One B-rep face of a CAD part: STEP entity #308.
In plain terms, the planar face has unit normal (1, 0, 0).
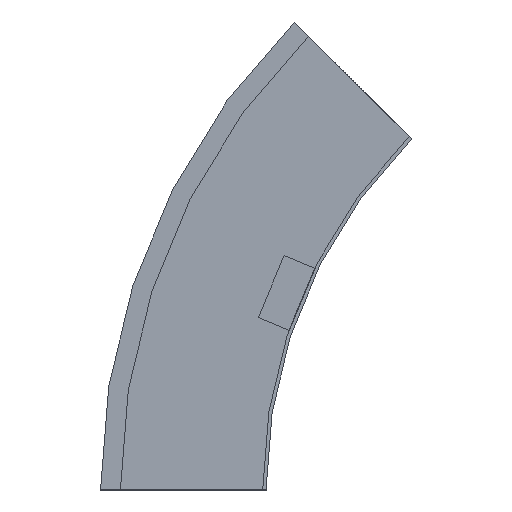
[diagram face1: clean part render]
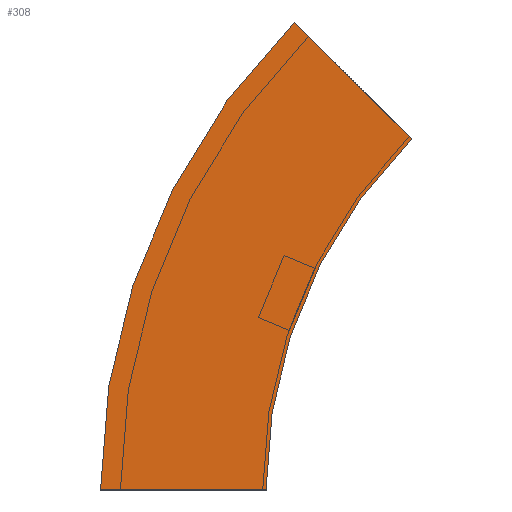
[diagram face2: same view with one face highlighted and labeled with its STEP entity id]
Its self-contained STEP definition (entity closure, numbers rounded to 3 decimals):
#50 = CARTESIAN_POINT ( 'NONE',  ( 0., -17.157, 282.843 ) ) ;
#55 = CIRCLE ( 'NONE', #179, 300. ) ;
#83 = CARTESIAN_POINT ( 'NONE',  ( 0., -300., 0. ) ) ;
#111 = EDGE_CURVE ( 'NONE', #306, #490, #560, .T. ) ;
#138 = DIRECTION ( 'NONE',  ( 0., 0.707, 0.707 ) ) ;
#150 = FACE_OUTER_BOUND ( 'NONE', #440, .T. ) ;
#179 = AXIS2_PLACEMENT_3D ( 'NONE', #83, #513, #252 ) ;
#220 = DIRECTION ( 'NONE',  ( 1., 0., 0. ) ) ;
#235 = CIRCLE ( 'NONE', #315, 400. ) ;
#252 = DIRECTION ( 'NONE',  ( 0., 1., 0. ) ) ;
#268 = EDGE_CURVE ( 'NONE', #329, #494, #563, .T. ) ;
#275 = DIRECTION ( 'NONE',  ( 1., 0., 0. ) ) ;
#286 = ORIENTED_EDGE ( 'NONE', *, *, #407, .T. ) ;
#306 = VERTEX_POINT ( 'NONE', #413 ) ;
#308 = ADVANCED_FACE ( 'NONE', ( #150 ), #336, .T. ) ;
#315 = AXIS2_PLACEMENT_3D ( 'NONE', #354, #220, #526 ) ;
#319 = CARTESIAN_POINT ( 'NONE',  ( 0., -87.868, 212.132 ) ) ;
#329 = VERTEX_POINT ( 'NONE', #406 ) ;
#332 = CARTESIAN_POINT ( 'NONE',  ( 0., 0., 0. ) ) ;
#336 = PLANE ( 'NONE',  #553 ) ;
#346 = CARTESIAN_POINT ( 'NONE',  ( 0., 100., 0. ) ) ;
#349 = CARTESIAN_POINT ( 'NONE',  ( 0., 0., 0. ) ) ;
#354 = CARTESIAN_POINT ( 'NONE',  ( 0., -300., 0. ) ) ;
#406 = CARTESIAN_POINT ( 'NONE',  ( 0., -87.868, 212.132 ) ) ;
#407 = EDGE_CURVE ( 'NONE', #490, #494, #235, .T. ) ;
#413 = CARTESIAN_POINT ( 'NONE',  ( 0., 0., 0. ) ) ;
#438 = VECTOR ( 'NONE', #516, 1000. ) ;
#439 = ORIENTED_EDGE ( 'NONE', *, *, #268, .F. ) ;
#440 = EDGE_LOOP ( 'NONE', ( #286, #439, #445, #550 ) ) ;
#443 = VECTOR ( 'NONE', #138, 1000. ) ;
#445 = ORIENTED_EDGE ( 'NONE', *, *, #500, .F. ) ;
#490 = VERTEX_POINT ( 'NONE', #346 ) ;
#494 = VERTEX_POINT ( 'NONE', #50 ) ;
#500 = EDGE_CURVE ( 'NONE', #306, #329, #55, .T. ) ;
#513 = DIRECTION ( 'NONE',  ( 1., 0., 0. ) ) ;
#516 = DIRECTION ( 'NONE',  ( 0., 1., 0. ) ) ;
#526 = DIRECTION ( 'NONE',  ( 0., 1., 0. ) ) ;
#545 = DIRECTION ( 'NONE',  ( 0., 0., -1. ) ) ;
#550 = ORIENTED_EDGE ( 'NONE', *, *, #111, .T. ) ;
#553 = AXIS2_PLACEMENT_3D ( 'NONE', #332, #275, #545 ) ;
#560 = LINE ( 'NONE', #349, #438 ) ;
#563 = LINE ( 'NONE', #319, #443 ) ;
